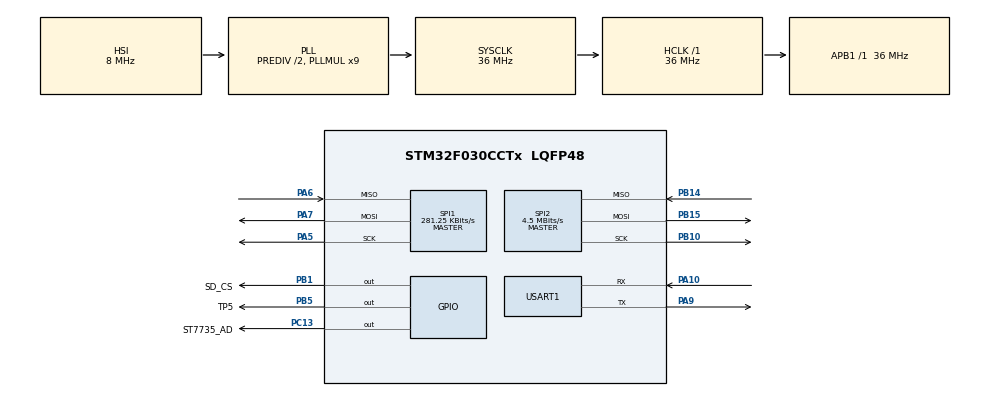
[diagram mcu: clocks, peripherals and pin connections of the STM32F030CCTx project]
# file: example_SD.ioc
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Dma.Request0=SPI1_RX
Dma.Request1=SPI1_TX
Dma.SPI1_RX.0.Direction=DMA_PERIPH_TO_MEMORY
Dma.SPI1_RX.0.Instance=DMA1_Channel2
Dma.SPI1_RX.0.MemDataAlignment=DMA_MDATAALIGN_BYTE
Dma.SPI1_RX.0.MemInc=DMA_MINC_ENABLE
Dma.SPI1_RX.0.Mode=DMA_NORMAL
Dma.SPI1_RX.0.PeriphDataAlignment=DMA_PDATAALIGN_BYTE
Dma.SPI1_RX.0.PeriphInc=DMA_PINC_DISABLE
Dma.SPI1_RX.0.Priority=DMA_PRIORITY_LOW
Dma.SPI1_TX.1.Direction=DMA_MEMORY_TO_PERIPH
Dma.SPI1_TX.1.Instance=DMA1_Channel3
Dma.SPI1_TX.1.MemDataAlignment=DMA_MDATAALIGN_BYTE
Dma.SPI1_TX.1.MemInc=DMA_MINC_ENABLE
Dma.SPI1_TX.1.Mode=DMA_NORMAL
Dma.SPI1_TX.1.PeriphDataAlignment=DMA_PDATAALIGN_BYTE
Dma.SPI1_TX.1.PeriphInc=DMA_PINC_DISABLE
Dma.SPI1_TX.1.Priority=DMA_PRIORITY_LOW
Mcu.Family=STM32F0
Mcu.Name=STM32F030CCTx
Mcu.Package=LQFP48
NVIC.DMA1_Channel2_3_IRQn=true\:0\:0\:false\:false\:true\:false\:true\:true
PA10.Mode=Asynchronous
PA10.Signal=USART1_RX
PA13.Mode=Serial_Wire
PA13.Signal=SYS_SWDIO
PA14.Mode=Serial_Wire
PA14.Signal=SYS_SWCLK
PA5.Mode=Full_Duplex_Master
PA5.Signal=SPI1_SCK
PA6.Mode=Full_Duplex_Master
PA6.Signal=SPI1_MISO
PA7.Mode=Full_Duplex_Master
PA7.Signal=SPI1_MOSI
PA9.Mode=Asynchronous
PA9.Signal=USART1_TX
PB1.GPIO_Label=SD_CS
PB1.Signal=GPIO_Output
PB10.Mode=Full_Duplex_Master
PB10.Signal=SPI2_SCK
PB14.Mode=Full_Duplex_Master
PB14.Signal=SPI2_MISO
PB15.Mode=Full_Duplex_Master
PB15.Signal=SPI2_MOSI
PB5.GPIO_Label=TP5
PB5.Signal=GPIO_Output
PC13.GPIO_Label=ST7735_AD
PC13.Signal=GPIO_Output
PC14OSC32_IN.GPIO_Label=ST7735_CS
PC14OSC32_IN.Signal=GPIO_Output
PC15OSC32_OUT.GPIO_Label=ST7735_RESET
PC15OSC32_OUT.Signal=GPIO_Output
ProjectManager.HeapSize=0x200
ProjectManager.StackSize=0x400
ProjectManager.TargetToolchain=STM32CubeIDE
RCC.AHBFreq_Value=36000000
RCC.APB1Freq_Value=36000000
RCC.APB1TimFreq_Value=36000000
RCC.HCLKFreq_Value=36000000
RCC.PLLDivider=RCC_PREDIV_DIV2
RCC.PLLMUL=RCC_PLL_MUL9
RCC.SYSCLKFreq_VALUE=36000000
RCC.SYSCLKSource=RCC_SYSCLKSOURCE_PLLCLK
SPI1.BaudRatePrescaler=SPI_BAUDRATEPRESCALER_128
SPI1.CalculateBaudRate=281.25 KBits/s
SPI1.DataSize=SPI_DATASIZE_8BIT
SPI1.Direction=SPI_DIRECTION_2LINES
SPI1.Mode=SPI_MODE_MASTER
SPI1.VirtualType=VM_MASTER
SPI2.BaudRatePrescaler=SPI_BAUDRATEPRESCALER_8
SPI2.CalculateBaudRate=4.5 MBits/s
SPI2.DataSize=SPI_DATASIZE_8BIT
SPI2.Direction=SPI_DIRECTION_2LINES
SPI2.Mode=SPI_MODE_MASTER
SPI2.VirtualType=VM_MASTER
USART1.VirtualMode-Asynchronous=VM_ASYNC
VP_FATFS_VS_Generic.Mode=User_defined
board=custom

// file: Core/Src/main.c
/* USER CODE BEGIN Header */
/**
  ******************************************************************************
  * @file           : main.c
  * @brief          : Main program body
  ******************************************************************************
  * @attention
  *
  * Copyright (c) 2024 STMicroelectronics.
  * All rights reserved.
  *
  * This software is licensed under terms that can be found in the LICENSE file
  * in the root directory of this software component.
  * If no LICENSE file comes with this software, it is provided AS-IS.
  *
  ******************************************************************************
  */
/* USER CODE END Header */
#include "main.h"
#include "fatfs.h"

/* USER CODE BEGIN Includes */
#include "sd_ex.h"
#include "ST7735.h"
#include "GFX_FUNCTIONS.h"
/* USER CODE END Includes */

SPI_HandleTypeDef hspi1;
SPI_HandleTypeDef hspi2;
DMA_HandleTypeDef hdma_spi1_rx;
DMA_HandleTypeDef hdma_spi1_tx;

UART_HandleTypeDef huart1;

void SystemClock_Config(void);
static void MX_GPIO_Init(void);
static void MX_DMA_Init(void);
static void MX_SPI1_Init(void);
static void MX_USART1_UART_Init(void);
static void MX_SPI2_Init(void);

int main(void)
{

  /* MCU Configuration--------------------------------------------------------*/

  /* Reset of all peripherals, Initializes the Flash interface and the Systick. */
  HAL_Init();

  /* Configure the system clock */
  SystemClock_Config();

  /* Initialize all configured peripherals */
  MX_GPIO_Init();
  MX_DMA_Init();
  MX_SPI1_Init();
  MX_USART1_UART_Init();
  MX_FATFS_Init();
  MX_SPI2_Init();
  /* USER CODE BEGIN 2 */

  ST7735_Init(0);

  fillScreen(BLACK);
  HAL_Delay(500);

  sd_process();

  HAL_Delay(1000); //a short delay is important to let the SD card settle

  /* USER CODE END 2 */

  /* Infinite loop */
  while(1)
  {

    /* USER CODE BEGIN 3 */

  	  HAL_Delay(1000);

  }

  /* USER CODE END 3 */
}

void SystemClock_Config(void)
{
  RCC_OscInitTypeDef RCC_OscInitStruct = {0};
  RCC_ClkInitTypeDef RCC_ClkInitStruct = {0};
  RCC_PeriphCLKInitTypeDef PeriphClkInit = {0};

  /** Initializes the RCC Oscillators according to the specified parameters
  * in the RCC_OscInitTypeDef structure.
  */
  RCC_OscInitStruct.OscillatorType = RCC_OSCILLATORTYPE_HSI;
  RCC_OscInitStruct.HSIState = RCC_HSI_ON;
  RCC_OscInitStruct.HSICalibrationValue = RCC_HSICALIBRATION_DEFAULT;
  RCC_OscInitStruct.PLL.PLLState = RCC_PLL_ON;
  RCC_OscInitStruct.PLL.PLLSource = RCC_PLLSOURCE_HSI;
  RCC_OscInitStruct.PLL.PLLMUL = RCC_PLL_MUL9;
  RCC_OscInitStruct.PLL.PREDIV = RCC_PREDIV_DIV2;
  if (HAL_RCC_OscConfig(&RCC_OscInitStruct) != HAL_OK)
  {
    Error_Handler();
  }

  /** Initializes the CPU, AHB and APB buses clocks
  */
  RCC_ClkInitStruct.ClockType = RCC_CLOCKTYPE_HCLK|RCC_CLOCKTYPE_SYSCLK
                              |RCC_CLOCKTYPE_PCLK1;
  RCC_ClkInitStruct.SYSCLKSource = RCC_SYSCLKSOURCE_PLLCLK;
  RCC_ClkInitStruct.AHBCLKDivider = RCC_SYSCLK_DIV1;
  RCC_ClkInitStruct.APB1CLKDivider = RCC_HCLK_DIV1;

  if (HAL_RCC_ClockConfig(&RCC_ClkInitStruct, FLASH_LATENCY_1) != HAL_OK)
  {
    Error_Handler();
  }
  PeriphClkInit.PeriphClockSelection = RCC_PERIPHCLK_USART1;
  PeriphClkInit.Usart1ClockSelection = RCC_USART1CLKSOURCE_PCLK1;
  if (HAL_RCCEx_PeriphCLKConfig(&PeriphClkInit) != HAL_OK)
  {
    Error_Handler();
  }
}

static void MX_SPI1_Init(void)
{

  /* SPI1 parameter configuration*/
  hspi1.Instance = SPI1;
  hspi1.Init.Mode = SPI_MODE_MASTER;
  hspi1.Init.Direction = SPI_DIRECTION_2LINES;
  hspi1.Init.DataSize = SPI_DATASIZE_8BIT;
  hspi1.Init.CLKPolarity = SPI_POLARITY_LOW;
  hspi1.Init.CLKPhase = SPI_PHASE_1EDGE;
  hspi1.Init.NSS = SPI_NSS_SOFT;
  hspi1.Init.BaudRatePrescaler = SPI_BAUDRATEPRESCALER_128;
  hspi1.Init.FirstBit = SPI_FIRSTBIT_MSB;
  hspi1.Init.TIMode = SPI_TIMODE_DISABLE;
  hspi1.Init.CRCCalculation = SPI_CRCCALCULATION_DISABLE;
  hspi1.Init.CRCPolynomial = 7;
  hspi1.Init.CRCLength = SPI_CRC_LENGTH_DATASIZE;
  hspi1.Init.NSSPMode = SPI_NSS_PULSE_ENABLE;
  if (HAL_SPI_Init(&hspi1) != HAL_OK)
  {
    Error_Handler();
  }

}

static void MX_SPI2_Init(void)
{

  /* SPI2 parameter configuration*/
  hspi2.Instance = SPI2;
  hspi2.Init.Mode = SPI_MODE_MASTER;
  hspi2.Init.Direction = SPI_DIRECTION_2LINES;
  hspi2.Init.DataSize = SPI_DATASIZE_8BIT;
  hspi2.Init.CLKPolarity = SPI_POLARITY_LOW;
  hspi2.Init.CLKPhase = SPI_PHASE_1EDGE;
  hspi2.Init.NSS = SPI_NSS_SOFT;
  hspi2.Init.BaudRatePrescaler = SPI_BAUDRATEPRESCALER_8;
  hspi2.Init.FirstBit = SPI_FIRSTBIT_MSB;
  hspi2.Init.TIMode = SPI_TIMODE_DISABLE;
  hspi2.Init.CRCCalculation = SPI_CRCCALCULATION_DISABLE;
  hspi2.Init.CRCPolynomial = 7;
  hspi2.Init.CRCLength = SPI_CRC_LENGTH_DATASIZE;
  hspi2.Init.NSSPMode = SPI_NSS_PULSE_ENABLE;
  if (HAL_SPI_Init(&hspi2) != HAL_OK)
  {
    Error_Handler();
  }

}

static void MX_USART1_UART_Init(void)
{

  huart1.Instance = USART1;
  huart1.Init.BaudRate = 115200;
  huart1.Init.WordLength = UART_WORDLENGTH_8B;
  huart1.Init.StopBits = UART_STOPBITS_1;
  huart1.Init.Parity = UART_PARITY_NONE;
  huart1.Init.Mode = UART_MODE_TX_RX;
  huart1.Init.HwFlowCtl = UART_HWCONTROL_NONE;
  huart1.Init.OverSampling = UART_OVERSAMPLING_16;
  huart1.Init.OneBitSampling = UART_ONE_BIT_SAMPLE_DISABLE;
  huart1.AdvancedInit.AdvFeatureInit = UART_ADVFEATURE_NO_INIT;
  if (HAL_UART_Init(&huart1) != HAL_OK)
  {
    Error_Handler();
  }

}

static void MX_DMA_Init(void)
{

  /* DMA controller clock enable */
  __HAL_RCC_DMA1_CLK_ENABLE();

  /* DMA interrupt init */
  /* DMA1_Channel2_3_IRQn interrupt configuration */
  HAL_NVIC_SetPriority(DMA1_Channel2_3_IRQn, 0, 0);
  HAL_NVIC_EnableIRQ(DMA1_Channel2_3_IRQn);

}

static void MX_GPIO_Init(void)
{
  GPIO_InitTypeDef GPIO_InitStruct = {0};

  /* GPIO Ports Clock Enable */
  __HAL_RCC_GPIOC_CLK_ENABLE();
  __HAL_RCC_GPIOA_CLK_ENABLE();
  __HAL_RCC_GPIOB_CLK_ENABLE();

  /*Configure GPIO pin Output Level */
  HAL_GPIO_WritePin(GPIOC, ST7735_AD_Pin|ST7735_CS_Pin|ST7735_RESET_Pin, GPIO_PIN_RESET);

  /*Configure GPIO pin Output Level */
  HAL_GPIO_WritePin(GPIOB, SD_CS_Pin|TP5_Pin, GPIO_PIN_RESET);

  /*Configure GPIO pins : ST7735_AD_Pin ST7735_CS_Pin ST7735_RESET_Pin */
  GPIO_InitStruct.Pin = ST7735_AD_Pin|ST7735_CS_Pin|ST7735_RESET_Pin;
  GPIO_InitStruct.Mode = GPIO_MODE_OUTPUT_PP;
  GPIO_InitStruct.Pull = GPIO_NOPULL;
  GPIO_InitStruct.Speed = GPIO_SPEED_FREQ_LOW;
  HAL_GPIO_Init(GPIOC, &GPIO_InitStruct);

  /*Configure GPIO pins : SD_CS_Pin TP5_Pin */
  GPIO_InitStruct.Pin = SD_CS_Pin|TP5_Pin;
  GPIO_InitStruct.Mode = GPIO_MODE_OUTPUT_PP;
  GPIO_InitStruct.Pull = GPIO_NOPULL;
  GPIO_InitStruct.Speed = GPIO_SPEED_FREQ_LOW;
  HAL_GPIO_Init(GPIOB, &GPIO_InitStruct);

}

void Error_Handler(void)
{
  __disable_irq();
  while (1)
  {
  }
}
